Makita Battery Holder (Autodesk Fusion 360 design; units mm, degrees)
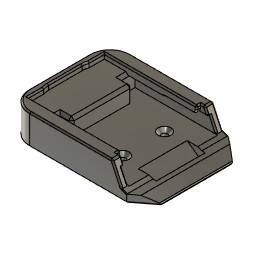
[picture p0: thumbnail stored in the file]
base_feature "Base Feature" bodies "Makita Battery Holder", "Holder"
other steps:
create_component "CreateComponent1"
named bodies: "Makita Battery Holder", "Holder"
